VERSION 5.7 ;
  NOWIREEXTENSIONATPIN ON ;
  DIVIDERCHAR "/" ;
  BUSBITCHARS "[]" ;
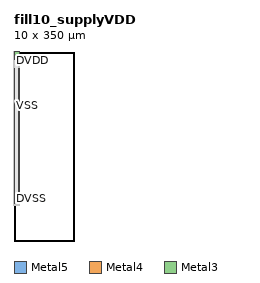
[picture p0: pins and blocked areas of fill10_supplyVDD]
MACRO fill10_supplyVDD
  CLASS PAD SPACER ;
  FOREIGN fill10_supplyVDD ;
  ORIGIN 0.000 0.000 ;
  SIZE 10.000 BY 350.000 ;
  SYMMETRY X Y R90 ;
  SITE GF_IO_Site ;
  PIN DVDD
    DIRECTION INOUT ;
    USE POWER ;
    PORT
      LAYER Metal5 ;
        RECT 0.000 118.000 1.000 125.000 ;
    END
    PORT
      LAYER Metal5 ;
        RECT 9.000 118.000 10.000 125.000 ;
    END
    PORT
      LAYER Metal5 ;
        RECT 0.000 134.000 1.000 149.000 ;
    END
    PORT
      LAYER Metal5 ;
        RECT 9.000 134.000 10.000 149.000 ;
    END
    PORT
      LAYER Metal5 ;
        RECT 0.000 150.000 1.000 165.000 ;
    END
    PORT
      LAYER Metal5 ;
        RECT 9.000 150.000 10.000 165.000 ;
    END
    PORT
      LAYER Metal5 ;
        RECT 0.000 166.000 1.000 181.000 ;
    END
    PORT
      LAYER Metal5 ;
        RECT 9.000 166.000 10.000 181.000 ;
    END
    PORT
      LAYER Metal5 ;
        RECT 0.000 182.000 1.000 197.000 ;
    END
    PORT
      LAYER Metal5 ;
        RECT 9.000 182.000 10.000 197.000 ;
    END
    PORT
      LAYER Metal5 ;
        RECT 0.000 206.000 1.000 213.000 ;
    END
    PORT
      LAYER Metal5 ;
        RECT 9.000 206.000 10.000 213.000 ;
    END
    PORT
      LAYER Metal5 ;
        RECT 0.000 214.000 1.000 229.000 ;
    END
    PORT
      LAYER Metal5 ;
        RECT 9.000 214.000 10.000 229.000 ;
    END
    PORT
      LAYER Metal5 ;
        RECT 0.000 254.000 1.000 261.000 ;
    END
    PORT
      LAYER Metal5 ;
        RECT 9.000 254.000 10.000 261.000 ;
    END
    PORT
      LAYER Metal5 ;
        RECT 0.000 262.000 1.000 269.000 ;
    END
    PORT
      LAYER Metal5 ;
        RECT 9.000 262.000 10.000 269.000 ;
    END
    PORT
      LAYER Metal5 ;
        RECT 0.000 270.000 1.000 277.000 ;
    END
    PORT
      LAYER Metal5 ;
        RECT 9.000 270.000 10.000 277.000 ;
    END
    PORT
      LAYER Metal5 ;
        RECT 0.000 278.000 1.000 285.000 ;
    END
    PORT
      LAYER Metal5 ;
        RECT 9.000 278.000 10.000 285.000 ;
    END
    PORT
      LAYER Metal5 ;
        RECT 0.000 294.000 1.000 301.000 ;
    END
    PORT
      LAYER Metal5 ;
        RECT 9.000 294.000 10.000 301.000 ;
    END
    PORT
      LAYER Metal5 ;
        RECT 0.000 310.000 1.000 317.000 ;
    END
    PORT
      LAYER Metal5 ;
        RECT 9.000 310.000 10.000 317.000 ;
    END
    PORT
      LAYER Metal5 ;
        RECT 0.000 334.000 1.000 341.000 ;
    END
    PORT
      LAYER Metal5 ;
        RECT 9.000 334.000 10.000 341.000 ;
    END
    PORT
      LAYER Metal5 ;
        RECT 0.485 341.000 9.485 350.000 ;
    END
    PORT
      LAYER Metal4 ;
        RECT 0.000 118.000 1.000 125.000 ;
    END
    PORT
      LAYER Metal4 ;
        RECT 9.000 118.000 10.000 125.000 ;
    END
    PORT
      LAYER Metal4 ;
        RECT 0.000 134.000 1.000 149.000 ;
    END
    PORT
      LAYER Metal4 ;
        RECT 9.000 134.000 10.000 149.000 ;
    END
    PORT
      LAYER Metal4 ;
        RECT 0.000 150.000 1.000 165.000 ;
    END
    PORT
      LAYER Metal4 ;
        RECT 9.000 150.000 10.000 165.000 ;
    END
    PORT
      LAYER Metal4 ;
        RECT 0.000 166.000 1.000 181.000 ;
    END
    PORT
      LAYER Metal4 ;
        RECT 9.000 166.000 10.000 181.000 ;
    END
    PORT
      LAYER Metal4 ;
        RECT 0.000 182.000 1.000 197.000 ;
    END
    PORT
      LAYER Metal4 ;
        RECT 9.000 182.000 10.000 197.000 ;
    END
    PORT
      LAYER Metal4 ;
        RECT 0.000 206.000 1.000 213.000 ;
    END
    PORT
      LAYER Metal4 ;
        RECT 9.000 206.000 10.000 213.000 ;
    END
    PORT
      LAYER Metal4 ;
        RECT 0.000 214.000 1.000 229.000 ;
    END
    PORT
      LAYER Metal4 ;
        RECT 9.000 214.000 10.000 229.000 ;
    END
    PORT
      LAYER Metal4 ;
        RECT 0.000 254.000 1.000 261.000 ;
    END
    PORT
      LAYER Metal4 ;
        RECT 9.000 254.000 10.000 261.000 ;
    END
    PORT
      LAYER Metal4 ;
        RECT 0.000 262.000 1.000 269.000 ;
    END
    PORT
      LAYER Metal4 ;
        RECT 9.000 262.000 10.000 269.000 ;
    END
    PORT
      LAYER Metal4 ;
        RECT 0.000 270.000 1.000 277.000 ;
    END
    PORT
      LAYER Metal4 ;
        RECT 9.000 270.000 10.000 277.000 ;
    END
    PORT
      LAYER Metal4 ;
        RECT 0.000 278.000 1.000 285.000 ;
    END
    PORT
      LAYER Metal4 ;
        RECT 9.000 278.000 10.000 285.000 ;
    END
    PORT
      LAYER Metal4 ;
        RECT 0.000 294.000 1.000 301.000 ;
    END
    PORT
      LAYER Metal4 ;
        RECT 9.000 294.000 10.000 301.000 ;
    END
    PORT
      LAYER Metal4 ;
        RECT 0.000 310.000 1.000 317.000 ;
    END
    PORT
      LAYER Metal4 ;
        RECT 9.000 310.000 10.000 317.000 ;
    END
    PORT
      LAYER Metal4 ;
        RECT 0.000 334.000 1.000 341.000 ;
    END
    PORT
      LAYER Metal4 ;
        RECT 9.000 334.000 10.000 341.000 ;
    END
    PORT
      LAYER Metal4 ;
        RECT 0.485 341.000 9.485 350.000 ;
    END
    PORT
      LAYER Metal3 ;
        RECT 0.000 118.000 1.000 125.000 ;
    END
    PORT
      LAYER Metal3 ;
        RECT 9.000 118.000 10.000 125.000 ;
    END
    PORT
      LAYER Metal3 ;
        RECT 0.000 134.000 1.000 149.000 ;
    END
    PORT
      LAYER Metal3 ;
        RECT 9.000 134.000 10.000 149.000 ;
    END
    PORT
      LAYER Metal3 ;
        RECT 0.000 150.000 1.000 165.000 ;
    END
    PORT
      LAYER Metal3 ;
        RECT 9.000 150.000 10.000 165.000 ;
    END
    PORT
      LAYER Metal3 ;
        RECT 0.000 166.000 1.000 181.000 ;
    END
    PORT
      LAYER Metal3 ;
        RECT 9.000 166.000 10.000 181.000 ;
    END
    PORT
      LAYER Metal3 ;
        RECT 0.000 182.000 1.000 197.000 ;
    END
    PORT
      LAYER Metal3 ;
        RECT 9.000 182.000 10.000 197.000 ;
    END
    PORT
      LAYER Metal3 ;
        RECT 0.000 206.000 1.000 213.000 ;
    END
    PORT
      LAYER Metal3 ;
        RECT 9.000 206.000 10.000 213.000 ;
    END
    PORT
      LAYER Metal3 ;
        RECT 0.000 214.000 1.000 229.000 ;
    END
    PORT
      LAYER Metal3 ;
        RECT 9.000 214.000 10.000 229.000 ;
    END
    PORT
      LAYER Metal3 ;
        RECT 0.000 254.000 1.000 261.000 ;
    END
    PORT
      LAYER Metal3 ;
        RECT 9.000 254.000 10.000 261.000 ;
    END
    PORT
      LAYER Metal3 ;
        RECT 0.000 262.000 1.000 269.000 ;
    END
    PORT
      LAYER Metal3 ;
        RECT 9.000 262.000 10.000 269.000 ;
    END
    PORT
      LAYER Metal3 ;
        RECT 0.000 270.000 1.000 277.000 ;
    END
    PORT
      LAYER Metal3 ;
        RECT 9.000 270.000 10.000 277.000 ;
    END
    PORT
      LAYER Metal3 ;
        RECT 0.000 278.000 1.000 285.000 ;
    END
    PORT
      LAYER Metal3 ;
        RECT 9.000 278.000 10.000 285.000 ;
    END
    PORT
      LAYER Metal3 ;
        RECT 0.000 294.000 1.000 301.000 ;
    END
    PORT
      LAYER Metal3 ;
        RECT 9.000 294.000 10.000 301.000 ;
    END
    PORT
      LAYER Metal3 ;
        RECT 0.000 310.000 1.000 317.000 ;
    END
    PORT
      LAYER Metal3 ;
        RECT 9.000 310.000 10.000 317.000 ;
    END
    PORT
      LAYER Metal3 ;
        RECT 0.000 334.000 1.000 341.000 ;
    END
    PORT
      LAYER Metal3 ;
        RECT 9.000 334.000 10.000 341.000 ;
    END
    PORT
      LAYER Metal3 ;
        RECT 0.485 341.000 9.485 350.000 ;
    END
  END DVDD
  PIN DVSS
    DIRECTION INOUT ;
    USE GROUND ;
    PORT
      LAYER Metal5 ;
        RECT 0.000 70.000 1.000 85.000 ;
    END
    PORT
      LAYER Metal5 ;
        RECT 9.000 70.000 10.000 85.000 ;
    END
    PORT
      LAYER Metal5 ;
        RECT 0.000 86.000 1.000 101.000 ;
    END
    PORT
      LAYER Metal5 ;
        RECT 9.000 86.000 10.000 101.000 ;
    END
    PORT
      LAYER Metal5 ;
        RECT 0.000 102.000 1.000 117.000 ;
    END
    PORT
      LAYER Metal5 ;
        RECT 9.000 102.000 10.000 117.000 ;
    END
    PORT
      LAYER Metal5 ;
        RECT 0.000 126.000 1.000 133.000 ;
    END
    PORT
      LAYER Metal5 ;
        RECT 9.000 126.000 10.000 133.000 ;
    END
    PORT
      LAYER Metal5 ;
        RECT 0.000 198.000 1.000 205.000 ;
    END
    PORT
      LAYER Metal5 ;
        RECT 9.000 198.000 10.000 205.000 ;
    END
    PORT
      LAYER Metal5 ;
        RECT 0.000 230.000 1.000 245.000 ;
    END
    PORT
      LAYER Metal5 ;
        RECT 9.000 230.000 10.000 245.000 ;
    END
    PORT
      LAYER Metal5 ;
        RECT 0.000 286.000 1.000 293.000 ;
    END
    PORT
      LAYER Metal5 ;
        RECT 9.000 286.000 10.000 293.000 ;
    END
    PORT
      LAYER Metal5 ;
        RECT 0.000 302.000 1.000 309.000 ;
    END
    PORT
      LAYER Metal5 ;
        RECT 9.000 302.000 10.000 309.000 ;
    END
    PORT
      LAYER Metal4 ;
        RECT 0.000 70.000 1.000 85.000 ;
    END
    PORT
      LAYER Metal4 ;
        RECT 9.000 70.000 10.000 85.000 ;
    END
    PORT
      LAYER Metal4 ;
        RECT 0.000 86.000 1.000 101.000 ;
    END
    PORT
      LAYER Metal4 ;
        RECT 9.000 86.000 10.000 101.000 ;
    END
    PORT
      LAYER Metal4 ;
        RECT 0.000 102.000 1.000 117.000 ;
    END
    PORT
      LAYER Metal4 ;
        RECT 9.000 102.000 10.000 117.000 ;
    END
    PORT
      LAYER Metal4 ;
        RECT 0.000 126.000 1.000 133.000 ;
    END
    PORT
      LAYER Metal4 ;
        RECT 9.000 126.000 10.000 133.000 ;
    END
    PORT
      LAYER Metal4 ;
        RECT 0.000 198.000 1.000 205.000 ;
    END
    PORT
      LAYER Metal4 ;
        RECT 9.000 198.000 10.000 205.000 ;
    END
    PORT
      LAYER Metal4 ;
        RECT 0.000 230.000 1.000 245.000 ;
    END
    PORT
      LAYER Metal4 ;
        RECT 9.000 230.000 10.000 245.000 ;
    END
    PORT
      LAYER Metal4 ;
        RECT 0.000 286.000 1.000 293.000 ;
    END
    PORT
      LAYER Metal4 ;
        RECT 9.000 286.000 10.000 293.000 ;
    END
    PORT
      LAYER Metal4 ;
        RECT 0.000 302.000 1.000 309.000 ;
    END
    PORT
      LAYER Metal4 ;
        RECT 9.000 302.000 10.000 309.000 ;
    END
    PORT
      LAYER Metal3 ;
        RECT 0.000 70.000 1.000 85.000 ;
    END
    PORT
      LAYER Metal3 ;
        RECT 9.000 70.000 10.000 85.000 ;
    END
    PORT
      LAYER Metal3 ;
        RECT 0.000 86.000 1.000 101.000 ;
    END
    PORT
      LAYER Metal3 ;
        RECT 9.000 86.000 10.000 101.000 ;
    END
    PORT
      LAYER Metal3 ;
        RECT 0.000 102.000 1.000 117.000 ;
    END
    PORT
      LAYER Metal3 ;
        RECT 9.000 102.000 10.000 117.000 ;
    END
    PORT
      LAYER Metal3 ;
        RECT 0.000 126.000 1.000 133.000 ;
    END
    PORT
      LAYER Metal3 ;
        RECT 9.000 126.000 10.000 133.000 ;
    END
    PORT
      LAYER Metal3 ;
        RECT 0.000 198.000 1.000 205.000 ;
    END
    PORT
      LAYER Metal3 ;
        RECT 9.000 198.000 10.000 205.000 ;
    END
    PORT
      LAYER Metal3 ;
        RECT 0.000 230.000 1.000 245.000 ;
    END
    PORT
      LAYER Metal3 ;
        RECT 9.000 230.000 10.000 245.000 ;
    END
    PORT
      LAYER Metal3 ;
        RECT 0.000 286.000 1.000 293.000 ;
    END
    PORT
      LAYER Metal3 ;
        RECT 9.000 286.000 10.000 293.000 ;
    END
    PORT
      LAYER Metal3 ;
        RECT 0.000 302.000 1.000 309.000 ;
    END
    PORT
      LAYER Metal3 ;
        RECT 9.000 302.000 10.000 309.000 ;
    END
  END DVSS
  PIN VSS
    DIRECTION INOUT ;
    USE GROUND ;
    PORT
      LAYER Metal5 ;
        RECT 0.000 246.000 1.000 253.000 ;
    END
    PORT
      LAYER Metal5 ;
        RECT 9.000 246.000 10.000 253.000 ;
    END
    PORT
      LAYER Metal4 ;
        RECT 0.000 246.000 1.000 253.000 ;
    END
    PORT
      LAYER Metal4 ;
        RECT 9.000 246.000 10.000 253.000 ;
    END
    PORT
      LAYER Metal3 ;
        RECT 0.000 246.000 1.000 253.000 ;
    END
    PORT
      LAYER Metal3 ;
        RECT 9.000 246.000 10.000 253.000 ;
    END
  END VSS
  OBS
      LAYER Nwell ;
        RECT 1.570 73.075 8.450 343.535 ;
      LAYER Metal1 ;
        RECT -0.160 65.540 10.160 349.785 ;
      LAYER Metal2 ;
        RECT 0.000 68.055 10.000 348.100 ;
      LAYER Metal3 ;
        RECT 1.000 70.000 9.000 341.000 ;
      LAYER Metal4 ;
        RECT 1.000 70.000 9.000 341.000 ;
      LAYER Metal5 ;
        RECT 1.000 70.000 9.000 341.000 ;
  END
END fill10_supplyVDD
END LIBRARY
